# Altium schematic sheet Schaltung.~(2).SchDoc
size A4

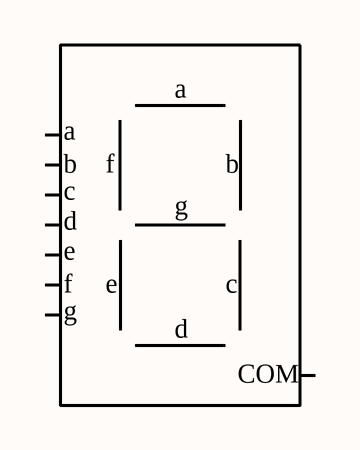
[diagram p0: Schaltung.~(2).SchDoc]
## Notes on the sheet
- a
- b
- f
- c
- d
- e
- g
- COM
